VERSION 5.7 ;
  NOWIREEXTENSIONATPIN ON ;
  DIVIDERCHAR "/" ;
  BUSBITCHARS "[]" ;
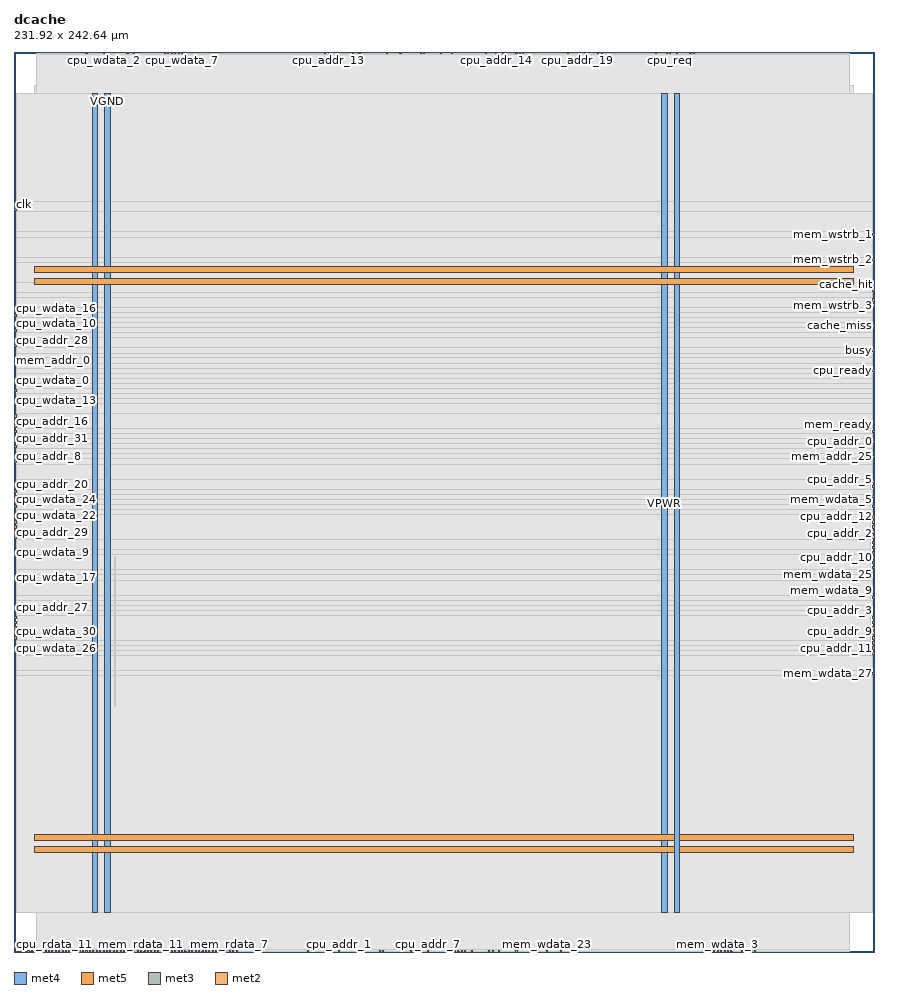
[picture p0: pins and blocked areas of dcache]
MACRO dcache
  CLASS BLOCK ;
  FOREIGN dcache ;
  ORIGIN 0.000 0.000 ;
  SIZE 231.920 BY 242.640 ;
  PIN VGND
    DIRECTION INOUT ;
    USE GROUND ;
    PORT
      LAYER met4 ;
        RECT 24.340 10.640 25.940 231.440 ;
    END
    PORT
      LAYER met4 ;
        RECT 177.940 10.640 179.540 231.440 ;
    END
    PORT
      LAYER met5 ;
        RECT 5.520 30.030 226.320 31.630 ;
    END
    PORT
      LAYER met5 ;
        RECT 5.520 183.210 226.320 184.810 ;
    END
  END VGND
  PIN VPWR
    DIRECTION INOUT ;
    USE POWER ;
    PORT
      LAYER met4 ;
        RECT 21.040 10.640 22.640 231.440 ;
    END
    PORT
      LAYER met4 ;
        RECT 174.640 10.640 176.240 231.440 ;
    END
    PORT
      LAYER met5 ;
        RECT 5.520 26.730 226.320 28.330 ;
    END
    PORT
      LAYER met5 ;
        RECT 5.520 179.910 226.320 181.510 ;
    END
  END VPWR
  PIN busy
    DIRECTION OUTPUT ;
    USE SIGNAL ;
    ANTENNAGATEAREA 0.434700 ;
    ANTENNADIFFAREA 0.434700 ;
    PORT
      LAYER met3 ;
        RECT 231.320 161.880 231.920 162.480 ;
    END
  END busy
  PIN cache_hit
    DIRECTION OUTPUT ;
    USE SIGNAL ;
    ANTENNAGATEAREA 0.434700 ;
    ANTENNADIFFAREA 1.137600 ;
    PORT
      LAYER met3 ;
        RECT 231.320 179.560 231.920 180.160 ;
    END
  END cache_hit
  PIN cache_miss
    DIRECTION OUTPUT ;
    USE SIGNAL ;
    ANTENNAGATEAREA 0.434700 ;
    ANTENNADIFFAREA 1.137600 ;
    PORT
      LAYER met3 ;
        RECT 231.320 168.680 231.920 169.280 ;
    END
  END cache_miss
  PIN clk
    DIRECTION INPUT ;
    USE SIGNAL ;
    ANTENNAGATEAREA 1.286700 ;
    ANTENNADIFFAREA 0.434700 ;
    PORT
      LAYER met3 ;
        RECT 0.000 201.320 0.600 201.920 ;
    END
  END clk
  PIN cpu_addr_0
    DIRECTION INPUT ;
    USE SIGNAL ;
    ANTENNAGATEAREA 0.647700 ;
    ANTENNADIFFAREA 0.434700 ;
    PORT
      LAYER met3 ;
        RECT 231.320 137.400 231.920 138.000 ;
    END
  END cpu_addr_0
  PIN cpu_addr_1
    DIRECTION INPUT ;
    USE SIGNAL ;
    ANTENNAGATEAREA 0.647700 ;
    ANTENNADIFFAREA 0.434700 ;
    PORT
      LAYER met2 ;
        RECT 87.490 0.000 87.770 0.280 ;
    END
  END cpu_addr_1
  PIN cpu_addr_10
    DIRECTION INPUT ;
    USE SIGNAL ;
    ANTENNAGATEAREA 0.647700 ;
    ANTENNADIFFAREA 0.434700 ;
    PORT
      LAYER met3 ;
        RECT 231.320 106.120 231.920 106.720 ;
    END
  END cpu_addr_10
  PIN cpu_addr_11
    DIRECTION INPUT ;
    USE SIGNAL ;
    ANTENNAGATEAREA 0.647700 ;
    ANTENNADIFFAREA 0.434700 ;
    PORT
      LAYER met3 ;
        RECT 231.320 81.640 231.920 82.240 ;
    END
  END cpu_addr_11
  PIN cpu_addr_12
    DIRECTION INPUT ;
    USE SIGNAL ;
    ANTENNAGATEAREA 0.647700 ;
    ANTENNADIFFAREA 0.434700 ;
    PORT
      LAYER met3 ;
        RECT 231.320 117.000 231.920 117.600 ;
    END
  END cpu_addr_12
  PIN cpu_addr_13
    DIRECTION INPUT ;
    USE SIGNAL ;
    ANTENNAGATEAREA 0.647700 ;
    ANTENNADIFFAREA 0.434700 ;
    PORT
      LAYER met2 ;
        RECT 84.730 242.360 85.010 242.640 ;
    END
  END cpu_addr_13
  PIN cpu_addr_14
    DIRECTION INPUT ;
    USE SIGNAL ;
    ANTENNAGATEAREA 0.647700 ;
    ANTENNADIFFAREA 0.434700 ;
    PORT
      LAYER met2 ;
        RECT 129.810 242.360 130.090 242.640 ;
    END
  END cpu_addr_14
  PIN cpu_addr_15
    DIRECTION INPUT ;
    USE SIGNAL ;
    ANTENNAGATEAREA 0.647700 ;
    ANTENNADIFFAREA 0.434700 ;
    PORT
      LAYER met2 ;
        RECT 110.490 242.360 110.770 242.640 ;
    END
  END cpu_addr_15
  PIN cpu_addr_16
    DIRECTION INPUT ;
    USE SIGNAL ;
    ANTENNAGATEAREA 0.647700 ;
    ANTENNADIFFAREA 0.434700 ;
    PORT
      LAYER met3 ;
        RECT 0.000 142.840 0.600 143.440 ;
    END
  END cpu_addr_16
  PIN cpu_addr_17
    DIRECTION INPUT ;
    USE SIGNAL ;
    ANTENNAGATEAREA 0.647700 ;
    ANTENNADIFFAREA 0.434700 ;
    PORT
      LAYER met2 ;
        RECT 130.730 242.360 131.010 242.640 ;
    END
  END cpu_addr_17
  PIN cpu_addr_18
    DIRECTION INPUT ;
    USE SIGNAL ;
    ANTENNAGATEAREA 0.647700 ;
    ANTENNADIFFAREA 0.434700 ;
    PORT
      LAYER met2 ;
        RECT 104.050 242.360 104.330 242.640 ;
    END
  END cpu_addr_18
  PIN cpu_addr_19
    DIRECTION INPUT ;
    USE SIGNAL ;
    ANTENNAGATEAREA 0.647700 ;
    ANTENNADIFFAREA 0.434700 ;
    PORT
      LAYER met2 ;
        RECT 151.890 242.360 152.170 242.640 ;
    END
  END cpu_addr_19
  PIN cpu_addr_2
    DIRECTION INPUT ;
    USE SIGNAL ;
    ANTENNAGATEAREA 0.647700 ;
    ANTENNADIFFAREA 0.434700 ;
    PORT
      LAYER met3 ;
        RECT 231.320 114.280 231.920 114.880 ;
    END
  END cpu_addr_2
  PIN cpu_addr_20
    DIRECTION INPUT ;
    USE SIGNAL ;
    ANTENNAGATEAREA 0.647700 ;
    ANTENNADIFFAREA 0.434700 ;
    PORT
      LAYER met3 ;
        RECT 0.000 123.800 0.600 124.400 ;
    END
  END cpu_addr_20
  PIN cpu_addr_21
    DIRECTION INPUT ;
    USE SIGNAL ;
    ANTENNAGATEAREA 0.647700 ;
    ANTENNADIFFAREA 0.434700 ;
    PORT
      LAYER met2 ;
        RECT 131.650 242.360 131.930 242.640 ;
    END
  END cpu_addr_21
  PIN cpu_addr_22
    DIRECTION INPUT ;
    USE SIGNAL ;
    ANTENNAGATEAREA 0.647700 ;
    ANTENNADIFFAREA 0.434700 ;
    PORT
      LAYER met2 ;
        RECT 40.570 242.360 40.850 242.640 ;
    END
  END cpu_addr_22
  PIN cpu_addr_23
    DIRECTION INPUT ;
    USE SIGNAL ;
    ANTENNAGATEAREA 0.647700 ;
    ANTENNADIFFAREA 0.434700 ;
    PORT
      LAYER met2 ;
        RECT 149.130 242.360 149.410 242.640 ;
    END
  END cpu_addr_23
  PIN cpu_addr_24
    DIRECTION INPUT ;
    USE SIGNAL ;
    ANTENNAGATEAREA 0.647700 ;
    ANTENNADIFFAREA 0.434700 ;
    PORT
      LAYER met2 ;
        RECT 99.450 0.000 99.730 0.280 ;
    END
  END cpu_addr_24
  PIN cpu_addr_25
    DIRECTION INPUT ;
    USE SIGNAL ;
    ANTENNAGATEAREA 0.647700 ;
    ANTENNADIFFAREA 0.434700 ;
    PORT
      LAYER met2 ;
        RECT 93.010 242.360 93.290 242.640 ;
    END
  END cpu_addr_25
  PIN cpu_addr_26
    DIRECTION INPUT ;
    USE SIGNAL ;
    ANTENNAGATEAREA 0.647700 ;
    ANTENNADIFFAREA 0.434700 ;
    PORT
      LAYER met2 ;
        RECT 115.090 242.360 115.370 242.640 ;
    END
  END cpu_addr_26
  PIN cpu_addr_27
    DIRECTION INPUT ;
    USE SIGNAL ;
    ANTENNAGATEAREA 0.647700 ;
    ANTENNADIFFAREA 0.434700 ;
    PORT
      LAYER met3 ;
        RECT 0.000 92.520 0.600 93.120 ;
    END
  END cpu_addr_27
  PIN cpu_addr_28
    DIRECTION INPUT ;
    USE SIGNAL ;
    ANTENNAGATEAREA 0.647700 ;
    ANTENNADIFFAREA 0.434700 ;
    PORT
      LAYER met3 ;
        RECT 0.000 164.600 0.600 165.200 ;
    END
  END cpu_addr_28
  PIN cpu_addr_29
    DIRECTION INPUT ;
    USE SIGNAL ;
    ANTENNAGATEAREA 0.647700 ;
    ANTENNADIFFAREA 0.434700 ;
    PORT
      LAYER met3 ;
        RECT 0.000 112.920 0.600 113.520 ;
    END
  END cpu_addr_29
  PIN cpu_addr_3
    DIRECTION INPUT ;
    USE SIGNAL ;
    ANTENNAGATEAREA 0.647700 ;
    ANTENNADIFFAREA 0.434700 ;
    PORT
      LAYER met3 ;
        RECT 231.320 89.800 231.920 90.400 ;
    END
  END cpu_addr_3
  PIN cpu_addr_30
    DIRECTION INPUT ;
    USE SIGNAL ;
    ANTENNAGATEAREA 0.647700 ;
    ANTENNADIFFAREA 0.434700 ;
    PORT
      LAYER met2 ;
        RECT 93.010 0.000 93.290 0.280 ;
    END
  END cpu_addr_30
  PIN cpu_addr_31
    DIRECTION INPUT ;
    USE SIGNAL ;
    ANTENNAGATEAREA 0.647700 ;
    ANTENNADIFFAREA 0.434700 ;
    PORT
      LAYER met3 ;
        RECT 0.000 140.120 0.600 140.720 ;
    END
  END cpu_addr_31
  PIN cpu_addr_4
    DIRECTION INPUT ;
    USE SIGNAL ;
    ANTENNAGATEAREA 0.647700 ;
    ANTENNADIFFAREA 0.434700 ;
    PORT
      LAYER met3 ;
        RECT 231.320 108.840 231.920 109.440 ;
    END
  END cpu_addr_4
  PIN cpu_addr_5
    DIRECTION INPUT ;
    USE SIGNAL ;
    ANTENNAGATEAREA 0.647700 ;
    ANTENNADIFFAREA 0.434700 ;
    PORT
      LAYER met3 ;
        RECT 231.320 125.160 231.920 125.760 ;
    END
  END cpu_addr_5
  PIN cpu_addr_6
    DIRECTION INPUT ;
    USE SIGNAL ;
    ANTENNAGATEAREA 0.647700 ;
    ANTENNADIFFAREA 0.434700 ;
    PORT
      LAYER met2 ;
        RECT 128.890 0.000 129.170 0.280 ;
    END
  END cpu_addr_6
  PIN cpu_addr_7
    DIRECTION INPUT ;
    USE SIGNAL ;
    ANTENNAGATEAREA 0.647700 ;
    ANTENNADIFFAREA 0.434700 ;
    PORT
      LAYER met2 ;
        RECT 111.410 0.000 111.690 0.280 ;
    END
  END cpu_addr_7
  PIN cpu_addr_8
    DIRECTION INPUT ;
    USE SIGNAL ;
    ANTENNAGATEAREA 0.647700 ;
    ANTENNADIFFAREA 0.434700 ;
    PORT
      LAYER met3 ;
        RECT 0.000 133.320 0.600 133.920 ;
    END
  END cpu_addr_8
  PIN cpu_addr_9
    DIRECTION INPUT ;
    USE SIGNAL ;
    ANTENNAGATEAREA 0.647700 ;
    ANTENNADIFFAREA 0.434700 ;
    PORT
      LAYER met3 ;
        RECT 231.320 84.360 231.920 84.960 ;
    END
  END cpu_addr_9
  PIN cpu_rdata_0
    DIRECTION OUTPUT ;
    USE SIGNAL ;
    PORT
      LAYER met2 ;
        RECT 1.930 0.000 2.210 0.280 ;
    END
  END cpu_rdata_0
  PIN cpu_rdata_1
    DIRECTION OUTPUT ;
    USE SIGNAL ;
    PORT
      LAYER met2 ;
        RECT 2.850 0.000 3.130 0.280 ;
    END
  END cpu_rdata_1
  PIN cpu_rdata_10
    DIRECTION OUTPUT ;
    USE SIGNAL ;
    PORT
      LAYER met2 ;
        RECT 3.770 0.000 4.050 0.280 ;
    END
  END cpu_rdata_10
  PIN cpu_rdata_11
    DIRECTION OUTPUT ;
    USE SIGNAL ;
    PORT
      LAYER met2 ;
        RECT 4.690 0.000 4.970 0.280 ;
    END
  END cpu_rdata_11
  PIN cpu_rdata_12
    DIRECTION OUTPUT ;
    USE SIGNAL ;
    PORT
      LAYER met2 ;
        RECT 5.610 0.000 5.890 0.280 ;
    END
  END cpu_rdata_12
  PIN cpu_rdata_13
    DIRECTION OUTPUT ;
    USE SIGNAL ;
    PORT
      LAYER met2 ;
        RECT 6.530 0.000 6.810 0.280 ;
    END
  END cpu_rdata_13
  PIN cpu_rdata_14
    DIRECTION OUTPUT ;
    USE SIGNAL ;
    PORT
      LAYER met2 ;
        RECT 7.450 0.000 7.730 0.280 ;
    END
  END cpu_rdata_14
  PIN cpu_rdata_15
    DIRECTION OUTPUT ;
    USE SIGNAL ;
    PORT
      LAYER met2 ;
        RECT 8.370 0.000 8.650 0.280 ;
    END
  END cpu_rdata_15
  PIN cpu_rdata_16
    DIRECTION OUTPUT ;
    USE SIGNAL ;
    PORT
      LAYER met2 ;
        RECT 9.290 0.000 9.570 0.280 ;
    END
  END cpu_rdata_16
  PIN cpu_rdata_17
    DIRECTION OUTPUT ;
    USE SIGNAL ;
    PORT
      LAYER met2 ;
        RECT 10.210 0.000 10.490 0.280 ;
    END
  END cpu_rdata_17
  PIN cpu_rdata_18
    DIRECTION OUTPUT ;
    USE SIGNAL ;
    PORT
      LAYER met2 ;
        RECT 11.130 0.000 11.410 0.280 ;
    END
  END cpu_rdata_18
  PIN cpu_rdata_19
    DIRECTION OUTPUT ;
    USE SIGNAL ;
    PORT
      LAYER met2 ;
        RECT 12.050 0.000 12.330 0.280 ;
    END
  END cpu_rdata_19
  PIN cpu_rdata_2
    DIRECTION OUTPUT ;
    USE SIGNAL ;
    PORT
      LAYER met2 ;
        RECT 12.970 0.000 13.250 0.280 ;
    END
  END cpu_rdata_2
  PIN cpu_rdata_20
    DIRECTION OUTPUT ;
    USE SIGNAL ;
    PORT
      LAYER met2 ;
        RECT 13.890 0.000 14.170 0.280 ;
    END
  END cpu_rdata_20
  PIN cpu_rdata_21
    DIRECTION OUTPUT ;
    USE SIGNAL ;
    PORT
      LAYER met2 ;
        RECT 14.810 0.000 15.090 0.280 ;
    END
  END cpu_rdata_21
  PIN cpu_rdata_22
    DIRECTION OUTPUT ;
    USE SIGNAL ;
    PORT
      LAYER met2 ;
        RECT 15.730 0.000 16.010 0.280 ;
    END
  END cpu_rdata_22
  PIN cpu_rdata_23
    DIRECTION OUTPUT ;
    USE SIGNAL ;
    PORT
      LAYER met2 ;
        RECT 16.650 0.000 16.930 0.280 ;
    END
  END cpu_rdata_23
  PIN cpu_rdata_24
    DIRECTION OUTPUT ;
    USE SIGNAL ;
    PORT
      LAYER met2 ;
        RECT 17.570 0.000 17.850 0.280 ;
    END
  END cpu_rdata_24
  PIN cpu_rdata_25
    DIRECTION OUTPUT ;
    USE SIGNAL ;
    PORT
      LAYER met2 ;
        RECT 18.490 0.000 18.770 0.280 ;
    END
  END cpu_rdata_25
  PIN cpu_rdata_26
    DIRECTION OUTPUT ;
    USE SIGNAL ;
    PORT
      LAYER met2 ;
        RECT 19.410 0.000 19.690 0.280 ;
    END
  END cpu_rdata_26
  PIN cpu_rdata_27
    DIRECTION OUTPUT ;
    USE SIGNAL ;
    PORT
      LAYER met2 ;
        RECT 20.330 0.000 20.610 0.280 ;
    END
  END cpu_rdata_27
  PIN cpu_rdata_28
    DIRECTION OUTPUT ;
    USE SIGNAL ;
    PORT
      LAYER met2 ;
        RECT 21.250 0.000 21.530 0.280 ;
    END
  END cpu_rdata_28
  PIN cpu_rdata_29
    DIRECTION OUTPUT ;
    USE SIGNAL ;
    PORT
      LAYER met2 ;
        RECT 22.170 0.000 22.450 0.280 ;
    END
  END cpu_rdata_29
  PIN cpu_rdata_3
    DIRECTION OUTPUT ;
    USE SIGNAL ;
    PORT
      LAYER met2 ;
        RECT 23.090 0.000 23.370 0.280 ;
    END
  END cpu_rdata_3
  PIN cpu_rdata_30
    DIRECTION OUTPUT ;
    USE SIGNAL ;
    PORT
      LAYER met2 ;
        RECT 24.010 0.000 24.290 0.280 ;
    END
  END cpu_rdata_30
  PIN cpu_rdata_31
    DIRECTION OUTPUT ;
    USE SIGNAL ;
    PORT
      LAYER met2 ;
        RECT 24.930 0.000 25.210 0.280 ;
    END
  END cpu_rdata_31
  PIN cpu_rdata_4
    DIRECTION OUTPUT ;
    USE SIGNAL ;
    PORT
      LAYER met2 ;
        RECT 25.850 0.000 26.130 0.280 ;
    END
  END cpu_rdata_4
  PIN cpu_rdata_5
    DIRECTION OUTPUT ;
    USE SIGNAL ;
    PORT
      LAYER met2 ;
        RECT 26.770 0.000 27.050 0.280 ;
    END
  END cpu_rdata_5
  PIN cpu_rdata_6
    DIRECTION OUTPUT ;
    USE SIGNAL ;
    PORT
      LAYER met2 ;
        RECT 27.690 0.000 27.970 0.280 ;
    END
  END cpu_rdata_6
  PIN cpu_rdata_7
    DIRECTION OUTPUT ;
    USE SIGNAL ;
    PORT
      LAYER met2 ;
        RECT 28.610 0.000 28.890 0.280 ;
    END
  END cpu_rdata_7
  PIN cpu_rdata_8
    DIRECTION OUTPUT ;
    USE SIGNAL ;
    PORT
      LAYER met2 ;
        RECT 29.530 0.000 29.810 0.280 ;
    END
  END cpu_rdata_8
  PIN cpu_rdata_9
    DIRECTION OUTPUT ;
    USE SIGNAL ;
    PORT
      LAYER met2 ;
        RECT 30.450 0.000 30.730 0.280 ;
    END
  END cpu_rdata_9
  PIN cpu_ready
    DIRECTION OUTPUT ;
    USE SIGNAL ;
    ANTENNAGATEAREA 0.434700 ;
    ANTENNADIFFAREA 1.137600 ;
    PORT
      LAYER met3 ;
        RECT 231.320 156.440 231.920 157.040 ;
    END
  END cpu_ready
  PIN cpu_req
    DIRECTION INPUT ;
    USE SIGNAL ;
    ANTENNAGATEAREA 0.647700 ;
    ANTENNADIFFAREA 0.434700 ;
    PORT
      LAYER met2 ;
        RECT 176.730 242.360 177.010 242.640 ;
    END
  END cpu_req
  PIN cpu_wdata_0
    DIRECTION INPUT ;
    USE SIGNAL ;
    ANTENNAGATEAREA 0.647700 ;
    ANTENNADIFFAREA 0.434700 ;
    PORT
      LAYER met3 ;
        RECT 0.000 153.720 0.600 154.320 ;
    END
  END cpu_wdata_0
  PIN cpu_wdata_1
    DIRECTION INPUT ;
    USE SIGNAL ;
    ANTENNAGATEAREA 0.647700 ;
    ANTENNADIFFAREA 0.434700 ;
    PORT
      LAYER met2 ;
        RECT 30.450 242.360 30.730 242.640 ;
    END
  END cpu_wdata_1
  PIN cpu_wdata_10
    DIRECTION INPUT ;
    USE SIGNAL ;
    ANTENNAGATEAREA 0.647700 ;
    ANTENNADIFFAREA 0.434700 ;
    PORT
      LAYER met3 ;
        RECT 0.000 167.320 0.600 167.920 ;
    END
  END cpu_wdata_10
  PIN cpu_wdata_11
    DIRECTION INPUT ;
    USE SIGNAL ;
    ANTENNAGATEAREA 0.647700 ;
    ANTENNADIFFAREA 0.434700 ;
    PORT
      LAYER met3 ;
        RECT 0.000 89.800 0.600 90.400 ;
    END
  END cpu_wdata_11
  PIN cpu_wdata_12
    DIRECTION INPUT ;
    USE SIGNAL ;
    ANTENNAGATEAREA 0.647700 ;
    ANTENNADIFFAREA 0.434700 ;
    PORT
      LAYER met3 ;
        RECT 0.000 168.680 0.600 169.280 ;
    END
  END cpu_wdata_12
  PIN cpu_wdata_13
    DIRECTION INPUT ;
    USE SIGNAL ;
    ANTENNAGATEAREA 0.647700 ;
    ANTENNADIFFAREA 0.434700 ;
    PORT
      LAYER met3 ;
        RECT 0.000 148.280 0.600 148.880 ;
    END
  END cpu_wdata_13
  PIN cpu_wdata_14
    DIRECTION INPUT ;
    USE SIGNAL ;
    ANTENNAGATEAREA 0.647700 ;
    ANTENNADIFFAREA 0.434700 ;
    PORT
      LAYER met2 ;
        RECT 44.250 242.360 44.530 242.640 ;
    END
  END cpu_wdata_14
  PIN cpu_wdata_15
    DIRECTION INPUT ;
    USE SIGNAL ;
    ANTENNAGATEAREA 0.647700 ;
    ANTENNADIFFAREA 0.434700 ;
    PORT
      LAYER met3 ;
        RECT 0.000 137.400 0.600 138.000 ;
    END
  END cpu_wdata_15
  PIN cpu_wdata_16
    DIRECTION INPUT ;
    USE SIGNAL ;
    ANTENNAGATEAREA 0.647700 ;
    ANTENNADIFFAREA 0.434700 ;
    PORT
      LAYER met3 ;
        RECT 0.000 171.400 0.600 172.000 ;
    END
  END cpu_wdata_16
  PIN cpu_wdata_17
    DIRECTION INPUT ;
    USE SIGNAL ;
    ANTENNAGATEAREA 0.647700 ;
    ANTENNADIFFAREA 0.434700 ;
    PORT
      LAYER met3 ;
        RECT 0.000 100.680 0.600 101.280 ;
    END
  END cpu_wdata_17
  PIN cpu_wdata_18
    DIRECTION INPUT ;
    USE SIGNAL ;
    ANTENNAGATEAREA 0.647700 ;
    ANTENNADIFFAREA 0.434700 ;
    PORT
      LAYER met3 ;
        RECT 0.000 151.000 0.600 151.600 ;
    END
  END cpu_wdata_18
  PIN cpu_wdata_19
    DIRECTION INPUT ;
    USE SIGNAL ;
    ANTENNAGATEAREA 0.647700 ;
    ANTENNADIFFAREA 0.434700 ;
    PORT
      LAYER met2 ;
        RECT 42.410 242.360 42.690 242.640 ;
    END
  END cpu_wdata_19
  PIN cpu_wdata_2
    DIRECTION INPUT ;
    USE SIGNAL ;
    ANTENNAGATEAREA 0.647700 ;
    ANTENNADIFFAREA 0.434700 ;
    PORT
      LAYER met2 ;
        RECT 24.010 242.360 24.290 242.640 ;
    END
  END cpu_wdata_2
  PIN cpu_wdata_20
    DIRECTION INPUT ;
    USE SIGNAL ;
    ANTENNAGATEAREA 0.647700 ;
    ANTENNADIFFAREA 0.434700 ;
    PORT
      LAYER met2 ;
        RECT 32.290 242.360 32.570 242.640 ;
    END
  END cpu_wdata_20
  PIN cpu_wdata_21
    DIRECTION INPUT ;
    USE SIGNAL ;
    ANTENNAGATEAREA 0.647700 ;
    ANTENNADIFFAREA 0.434700 ;
    PORT
      LAYER met3 ;
        RECT 0.000 87.080 0.600 87.680 ;
    END
  END cpu_wdata_21
  PIN cpu_wdata_22
    DIRECTION INPUT ;
    USE SIGNAL ;
    ANTENNAGATEAREA 0.647700 ;
    ANTENNADIFFAREA 0.434700 ;
    PORT
      LAYER met3 ;
        RECT 0.000 115.640 0.600 116.240 ;
    END
  END cpu_wdata_22
  PIN cpu_wdata_23
    DIRECTION INPUT ;
    USE SIGNAL ;
    ANTENNAGATEAREA 0.647700 ;
    ANTENNADIFFAREA 0.434700 ;
    PORT
      LAYER met2 ;
        RECT 24.930 242.360 25.210 242.640 ;
    END
  END cpu_wdata_23
  PIN cpu_wdata_24
    DIRECTION INPUT ;
    USE SIGNAL ;
    ANTENNAGATEAREA 0.647700 ;
    ANTENNADIFFAREA 0.434700 ;
    PORT
      LAYER met3 ;
        RECT 0.000 119.720 0.600 120.320 ;
    END
  END cpu_wdata_24
  PIN cpu_wdata_25
    DIRECTION INPUT ;
    USE SIGNAL ;
    ANTENNAGATEAREA 0.647700 ;
    ANTENNADIFFAREA 0.434700 ;
    PORT
      LAYER met3 ;
        RECT 0.000 111.560 0.600 112.160 ;
    END
  END cpu_wdata_25
  PIN cpu_wdata_26
    DIRECTION INPUT ;
    USE SIGNAL ;
    ANTENNAGATEAREA 0.647700 ;
    ANTENNADIFFAREA 0.434700 ;
    PORT
      LAYER met3 ;
        RECT 0.000 81.640 0.600 82.240 ;
    END
  END cpu_wdata_26
  PIN cpu_wdata_27
    DIRECTION INPUT ;
    USE SIGNAL ;
    ANTENNAGATEAREA 0.647700 ;
    ANTENNADIFFAREA 0.434700 ;
    PORT
      LAYER met3 ;
        RECT 0.000 88.440 0.600 89.040 ;
    END
  END cpu_wdata_27
  PIN cpu_wdata_28
    DIRECTION INPUT ;
    USE SIGNAL ;
    ANTENNAGATEAREA 0.647700 ;
    ANTENNADIFFAREA 0.434700 ;
    PORT
      LAYER met3 ;
        RECT 0.000 117.000 0.600 117.600 ;
    END
  END cpu_wdata_28
  PIN cpu_wdata_29
    DIRECTION INPUT ;
    USE SIGNAL ;
    ANTENNAGATEAREA 0.647700 ;
    ANTENNADIFFAREA 0.434700 ;
    PORT
      LAYER met2 ;
        RECT 19.410 242.360 19.690 242.640 ;
    END
  END cpu_wdata_29
  PIN cpu_wdata_3
    DIRECTION INPUT ;
    USE SIGNAL ;
    ANTENNAGATEAREA 0.647700 ;
    ANTENNADIFFAREA 0.434700 ;
    PORT
      LAYER met3 ;
        RECT 0.000 131.960 0.600 132.560 ;
    END
  END cpu_wdata_3
  PIN cpu_wdata_30
    DIRECTION INPUT ;
    USE SIGNAL ;
    ANTENNAGATEAREA 0.647700 ;
    ANTENNADIFFAREA 0.434700 ;
    PORT
      LAYER met3 ;
        RECT 0.000 84.360 0.600 84.960 ;
    END
  END cpu_wdata_30
  PIN cpu_wdata_31
    DIRECTION INPUT ;
    USE SIGNAL ;
    ANTENNAGATEAREA 0.647700 ;
    ANTENNADIFFAREA 0.434700 ;
    PORT
      LAYER met2 ;
        RECT 157.410 242.360 157.690 242.640 ;
    END
  END cpu_wdata_31
  PIN cpu_wdata_4
    DIRECTION INPUT ;
    USE SIGNAL ;
    ANTENNAGATEAREA 0.647700 ;
    ANTENNADIFFAREA 0.434700 ;
    PORT
      LAYER met2 ;
        RECT 43.330 242.360 43.610 242.640 ;
    END
  END cpu_wdata_4
  PIN cpu_wdata_5
    DIRECTION INPUT ;
    USE SIGNAL ;
    ANTENNAGATEAREA 0.647700 ;
    ANTENNADIFFAREA 0.434700 ;
    PORT
      LAYER met3 ;
        RECT 0.000 136.040 0.600 136.640 ;
    END
  END cpu_wdata_5
  PIN cpu_wdata_6
    DIRECTION INPUT ;
    USE SIGNAL ;
    ANTENNAGATEAREA 0.647700 ;
    ANTENNADIFFAREA 0.434700 ;
    PORT
      LAYER met3 ;
        RECT 0.000 85.720 0.600 86.320 ;
    END
  END cpu_wdata_6
  PIN cpu_wdata_7
    DIRECTION INPUT ;
    USE SIGNAL ;
    ANTENNAGATEAREA 0.647700 ;
    ANTENNADIFFAREA 0.434700 ;
    PORT
      LAYER met2 ;
        RECT 45.170 242.360 45.450 242.640 ;
    END
  END cpu_wdata_7
  PIN cpu_wdata_8
    DIRECTION INPUT ;
    USE SIGNAL ;
    ANTENNAGATEAREA 0.647700 ;
    ANTENNADIFFAREA 0.434700 ;
    PORT
      LAYER met3 ;
        RECT 0.000 144.200 0.600 144.800 ;
    END
  END cpu_wdata_8
  PIN cpu_wdata_9
    DIRECTION INPUT ;
    USE SIGNAL ;
    ANTENNAGATEAREA 0.647700 ;
    ANTENNADIFFAREA 0.434700 ;
    PORT
      LAYER met3 ;
        RECT 0.000 107.480 0.600 108.080 ;
    END
  END cpu_wdata_9
  PIN cpu_wstrb_0
    DIRECTION INPUT ;
    USE SIGNAL ;
    ANTENNAGATEAREA 0.647700 ;
    ANTENNADIFFAREA 0.434700 ;
    PORT
      LAYER met2 ;
        RECT 183.170 242.360 183.450 242.640 ;
    END
  END cpu_wstrb_0
  PIN cpu_wstrb_1
    DIRECTION INPUT ;
    USE SIGNAL ;
    ANTENNAGATEAREA 0.647700 ;
    ANTENNADIFFAREA 0.434700 ;
    PORT
      LAYER met2 ;
        RECT 182.250 242.360 182.530 242.640 ;
    END
  END cpu_wstrb_1
  PIN cpu_wstrb_2
    DIRECTION INPUT ;
    USE SIGNAL ;
    ANTENNAGATEAREA 0.647700 ;
    ANTENNADIFFAREA 0.434700 ;
    PORT
      LAYER met2 ;
        RECT 178.570 242.360 178.850 242.640 ;
    END
  END cpu_wstrb_2
  PIN cpu_wstrb_3
    DIRECTION INPUT ;
    USE SIGNAL ;
    ANTENNAGATEAREA 0.647700 ;
    ANTENNADIFFAREA 0.434700 ;
    PORT
      LAYER met2 ;
        RECT 173.050 242.360 173.330 242.640 ;
    END
  END cpu_wstrb_3
  PIN flush
    DIRECTION INPUT ;
    USE SIGNAL ;
    ANTENNAGATEAREA 0.647700 ;
    ANTENNADIFFAREA 0.434700 ;
    PORT
      LAYER met2 ;
        RECT 175.810 242.360 176.090 242.640 ;
    END
  END flush
  PIN mem_addr_0
    DIRECTION OUTPUT ;
    USE SIGNAL ;
    ANTENNAGATEAREA 0.434700 ;
    ANTENNADIFFAREA 1.137600 ;
    PORT
      LAYER met3 ;
        RECT 0.000 159.160 0.600 159.760 ;
    END
  END mem_addr_0
  PIN mem_addr_1
    DIRECTION OUTPUT ;
    USE SIGNAL ;
    ANTENNAGATEAREA 0.434700 ;
    ANTENNADIFFAREA 1.137600 ;
    PORT
      LAYER met2 ;
        RECT 41.490 242.360 41.770 242.640 ;
    END
  END mem_addr_1
  PIN mem_addr_10
    DIRECTION OUTPUT ;
    USE SIGNAL ;
    ANTENNAGATEAREA 0.434700 ;
    ANTENNADIFFAREA 1.137600 ;
    PORT
      LAYER met2 ;
        RECT 153.730 242.360 154.010 242.640 ;
    END
  END mem_addr_10
  PIN mem_addr_11
    DIRECTION OUTPUT ;
    USE SIGNAL ;
    ANTENNAGATEAREA 0.434700 ;
    ANTENNADIFFAREA 1.137600 ;
    PORT
      LAYER met2 ;
        RECT 83.810 242.360 84.090 242.640 ;
    END
  END mem_addr_11
  PIN mem_addr_12
    DIRECTION OUTPUT ;
    USE SIGNAL ;
    ANTENNAGATEAREA 0.434700 ;
    ANTENNADIFFAREA 1.137600 ;
    PORT
      LAYER met2 ;
        RECT 135.330 242.360 135.610 242.640 ;
    END
  END mem_addr_12
  PIN mem_addr_13
    DIRECTION OUTPUT ;
    USE SIGNAL ;
    ANTENNAGATEAREA 0.434700 ;
    ANTENNADIFFAREA 1.137600 ;
    PORT
      LAYER met3 ;
        RECT 0.000 122.440 0.600 123.040 ;
    END
  END mem_addr_13
  PIN mem_addr_14
    DIRECTION OUTPUT ;
    USE SIGNAL ;
    ANTENNAGATEAREA 0.434700 ;
    ANTENNADIFFAREA 1.137600 ;
    PORT
      LAYER met2 ;
        RECT 158.330 242.360 158.610 242.640 ;
    END
  END mem_addr_14
  PIN mem_addr_15
    DIRECTION OUTPUT ;
    USE SIGNAL ;
    ANTENNAGATEAREA 0.434700 ;
    ANTENNADIFFAREA 1.137600 ;
    PORT
      LAYER met2 ;
        RECT 109.570 242.360 109.850 242.640 ;
    END
  END mem_addr_15
  PIN mem_addr_16
    DIRECTION OUTPUT ;
    USE SIGNAL ;
    ANTENNAGATEAREA 0.434700 ;
    ANTENNADIFFAREA 1.137600 ;
    PORT
      LAYER met2 ;
        RECT 136.250 242.360 136.530 242.640 ;
    END
  END mem_addr_16
  PIN mem_addr_17
    DIRECTION OUTPUT ;
    USE SIGNAL ;
    ANTENNAGATEAREA 0.434700 ;
    ANTENNADIFFAREA 1.137600 ;
    PORT
      LAYER met3 ;
        RECT 0.000 141.480 0.600 142.080 ;
    END
  END mem_addr_17
  PIN mem_addr_18
    DIRECTION OUTPUT ;
    USE SIGNAL ;
    ANTENNAGATEAREA 0.434700 ;
    ANTENNADIFFAREA 1.137600 ;
    PORT
      LAYER met2 ;
        RECT 117.850 242.360 118.130 242.640 ;
    END
  END mem_addr_18
  PIN mem_addr_19
    DIRECTION OUTPUT ;
    USE SIGNAL ;
    ANTENNAGATEAREA 0.434700 ;
    ANTENNADIFFAREA 1.137600 ;
    PORT
      LAYER met2 ;
        RECT 137.170 242.360 137.450 242.640 ;
    END
  END mem_addr_19
  PIN mem_addr_2
    DIRECTION OUTPUT ;
    USE SIGNAL ;
    ANTENNAGATEAREA 0.434700 ;
    ANTENNADIFFAREA 1.137600 ;
    PORT
      LAYER met3 ;
        RECT 0.000 138.760 0.600 139.360 ;
    END
  END mem_addr_2
  PIN mem_addr_20
    DIRECTION OUTPUT ;
    USE SIGNAL ;
    ANTENNAGATEAREA 0.434700 ;
    ANTENNADIFFAREA 1.137600 ;
    PORT
      LAYER met2 ;
        RECT 91.170 242.360 91.450 242.640 ;
    END
  END mem_addr_20
  PIN mem_addr_21
    DIRECTION OUTPUT ;
    USE SIGNAL ;
    ANTENNAGATEAREA 0.434700 ;
    ANTENNADIFFAREA 1.137600 ;
    PORT
      LAYER met3 ;
        RECT 231.320 111.560 231.920 112.160 ;
    END
  END mem_addr_21
  PIN mem_addr_22
    DIRECTION OUTPUT ;
    USE SIGNAL ;
    ANTENNAGATEAREA 0.434700 ;
    ANTENNADIFFAREA 1.137600 ;
    PORT
      LAYER met3 ;
        RECT 231.320 80.280 231.920 80.880 ;
    END
  END mem_addr_22
  PIN mem_addr_23
    DIRECTION OUTPUT ;
    USE SIGNAL ;
    ANTENNAGATEAREA 0.434700 ;
    ANTENNADIFFAREA 1.137600 ;
    PORT
      LAYER met3 ;
        RECT 231.320 104.760 231.920 105.360 ;
    END
  END mem_addr_23
  PIN mem_addr_24
    DIRECTION OUTPUT ;
    USE SIGNAL ;
    ANTENNAGATEAREA 0.434700 ;
    ANTENNADIFFAREA 1.137600 ;
    PORT
      LAYER met3 ;
        RECT 231.320 83.000 231.920 83.600 ;
    END
  END mem_addr_24
  PIN mem_addr_25
    DIRECTION OUTPUT ;
    USE SIGNAL ;
    ANTENNAGATEAREA 0.434700 ;
    ANTENNADIFFAREA 1.137600 ;
    PORT
      LAYER met3 ;
        RECT 231.320 133.320 231.920 133.920 ;
    END
  END mem_addr_25
  PIN mem_addr_26
    DIRECTION OUTPUT ;
    USE SIGNAL ;
    ANTENNAGATEAREA 0.434700 ;
    ANTENNADIFFAREA 1.137600 ;
    PORT
      LAYER met2 ;
        RECT 118.770 0.000 119.050 0.280 ;
    END
  END mem_addr_26
  PIN mem_addr_27
    DIRECTION OUTPUT ;
    USE SIGNAL ;
    ANTENNAGATEAREA 0.434700 ;
    ANTENNADIFFAREA 1.137600 ;
    PORT
      LAYER met2 ;
        RECT 135.330 0.000 135.610 0.280 ;
    END
  END mem_addr_27
  PIN mem_addr_28
    DIRECTION OUTPUT ;
    USE SIGNAL ;
    ANTENNAGATEAREA 0.434700 ;
    ANTENNADIFFAREA 1.137600 ;
    PORT
      LAYER met3 ;
        RECT 231.320 126.520 231.920 127.120 ;
    END
  END mem_addr_28
  PIN mem_addr_29
    DIRECTION OUTPUT ;
    USE SIGNAL ;
    ANTENNAGATEAREA 0.434700 ;
    ANTENNADIFFAREA 1.137600 ;
    PORT
      LAYER met3 ;
        RECT 231.320 107.480 231.920 108.080 ;
    END
  END mem_addr_29
  PIN mem_addr_3
    DIRECTION OUTPUT ;
    USE SIGNAL ;
    ANTENNAGATEAREA 0.434700 ;
    ANTENNADIFFAREA 1.137600 ;
    PORT
      LAYER met2 ;
        RECT 98.530 0.000 98.810 0.280 ;
    END
  END mem_addr_3
  PIN mem_addr_30
    DIRECTION OUTPUT ;
    USE SIGNAL ;
    ANTENNAGATEAREA 0.434700 ;
    ANTENNADIFFAREA 1.137600 ;
    PORT
      LAYER met3 ;
        RECT 231.320 88.440 231.920 89.040 ;
    END
  END mem_addr_30
  PIN mem_addr_31
    DIRECTION OUTPUT ;
    USE SIGNAL ;
    ANTENNAGATEAREA 0.434700 ;
    ANTENNADIFFAREA 1.137600 ;
    PORT
      LAYER met3 ;
        RECT 231.320 112.920 231.920 113.520 ;
    END
  END mem_addr_31
  PIN mem_addr_4
    DIRECTION OUTPUT ;
    USE SIGNAL ;
    ANTENNAGATEAREA 0.434700 ;
    ANTENNADIFFAREA 1.137600 ;
    PORT
      LAYER met3 ;
        RECT 0.000 114.280 0.600 114.880 ;
    END
  END mem_addr_4
  PIN mem_addr_5
    DIRECTION OUTPUT ;
    USE SIGNAL ;
    ANTENNAGATEAREA 0.434700 ;
    ANTENNADIFFAREA 1.137600 ;
    PORT
      LAYER met3 ;
        RECT 0.000 163.240 0.600 163.840 ;
    END
  END mem_addr_5
  PIN mem_addr_6
    DIRECTION OUTPUT ;
    USE SIGNAL ;
    ANTENNAGATEAREA 0.434700 ;
    ANTENNADIFFAREA 1.137600 ;
    PORT
      LAYER met2 ;
        RECT 79.210 0.000 79.490 0.280 ;
    END
  END mem_addr_6
  PIN mem_addr_7
    DIRECTION OUTPUT ;
    USE SIGNAL ;
    ANTENNAGATEAREA 0.434700 ;
    ANTENNADIFFAREA 1.137600 ;
    PORT
      LAYER met2 ;
        RECT 127.050 242.360 127.330 242.640 ;
    END
  END mem_addr_7
  PIN mem_addr_8
    DIRECTION OUTPUT ;
    USE SIGNAL ;
    ANTENNAGATEAREA 0.434700 ;
    ANTENNADIFFAREA 1.137600 ;
    PORT
      LAYER met2 ;
        RECT 100.370 242.360 100.650 242.640 ;
    END
  END mem_addr_8
  PIN mem_addr_9
    DIRECTION OUTPUT ;
    USE SIGNAL ;
    ANTENNAGATEAREA 0.434700 ;
    ANTENNADIFFAREA 1.137600 ;
    PORT
      LAYER met2 ;
        RECT 106.810 0.000 107.090 0.280 ;
    END
  END mem_addr_9
  PIN mem_rdata_0
    DIRECTION INPUT ;
    USE SIGNAL ;
    PORT
      LAYER met2 ;
        RECT 31.370 0.000 31.650 0.280 ;
    END
  END mem_rdata_0
  PIN mem_rdata_1
    DIRECTION INPUT ;
    USE SIGNAL ;
    PORT
      LAYER met2 ;
        RECT 32.290 0.000 32.570 0.280 ;
    END
  END mem_rdata_1
  PIN mem_rdata_10
    DIRECTION INPUT ;
    USE SIGNAL ;
    PORT
      LAYER met2 ;
        RECT 33.210 0.000 33.490 0.280 ;
    END
  END mem_rdata_10
  PIN mem_rdata_11
    DIRECTION INPUT ;
    USE SIGNAL ;
    PORT
      LAYER met2 ;
        RECT 34.130 0.000 34.410 0.280 ;
    END
  END mem_rdata_11
  PIN mem_rdata_12
    DIRECTION INPUT ;
    USE SIGNAL ;
    PORT
      LAYER met2 ;
        RECT 35.050 0.000 35.330 0.280 ;
    END
  END mem_rdata_12
  PIN mem_rdata_13
    DIRECTION INPUT ;
    USE SIGNAL ;
    PORT
      LAYER met2 ;
        RECT 35.970 0.000 36.250 0.280 ;
    END
  END mem_rdata_13
  PIN mem_rdata_14
    DIRECTION INPUT ;
    USE SIGNAL ;
    PORT
      LAYER met2 ;
        RECT 36.890 0.000 37.170 0.280 ;
    END
  END mem_rdata_14
  PIN mem_rdata_15
    DIRECTION INPUT ;
    USE SIGNAL ;
    PORT
      LAYER met2 ;
        RECT 37.810 0.000 38.090 0.280 ;
    END
  END mem_rdata_15
  PIN mem_rdata_16
    DIRECTION INPUT ;
    USE SIGNAL ;
    PORT
      LAYER met2 ;
        RECT 38.730 0.000 39.010 0.280 ;
    END
  END mem_rdata_16
  PIN mem_rdata_17
    DIRECTION INPUT ;
    USE SIGNAL ;
    PORT
      LAYER met2 ;
        RECT 39.650 0.000 39.930 0.280 ;
    END
  END mem_rdata_17
  PIN mem_rdata_18
    DIRECTION INPUT ;
    USE SIGNAL ;
    PORT
      LAYER met2 ;
        RECT 40.570 0.000 40.850 0.280 ;
    END
  END mem_rdata_18
  PIN mem_rdata_19
    DIRECTION INPUT ;
    USE SIGNAL ;
    PORT
      LAYER met2 ;
        RECT 41.490 0.000 41.770 0.280 ;
    END
  END mem_rdata_19
  PIN mem_rdata_2
    DIRECTION INPUT ;
    USE SIGNAL ;
    PORT
      LAYER met2 ;
        RECT 42.410 0.000 42.690 0.280 ;
    END
  END mem_rdata_2
  PIN mem_rdata_20
    DIRECTION INPUT ;
    USE SIGNAL ;
    PORT
      LAYER met2 ;
        RECT 43.330 0.000 43.610 0.280 ;
    END
  END mem_rdata_20
  PIN mem_rdata_21
    DIRECTION INPUT ;
    USE SIGNAL ;
    PORT
      LAYER met2 ;
        RECT 44.250 0.000 44.530 0.280 ;
    END
  END mem_rdata_21
  PIN mem_rdata_22
    DIRECTION INPUT ;
    USE SIGNAL ;
    PORT
      LAYER met2 ;
        RECT 45.170 0.000 45.450 0.280 ;
    END
  END mem_rdata_22
  PIN mem_rdata_23
    DIRECTION INPUT ;
    USE SIGNAL ;
    PORT
      LAYER met2 ;
        RECT 46.090 0.000 46.370 0.280 ;
    END
  END mem_rdata_23
  PIN mem_rdata_24
    DIRECTION INPUT ;
    USE SIGNAL ;
    PORT
      LAYER met2 ;
        RECT 47.010 0.000 47.290 0.280 ;
    END
  END mem_rdata_24
  PIN mem_rdata_25
    DIRECTION INPUT ;
    USE SIGNAL ;
    PORT
      LAYER met2 ;
        RECT 47.930 0.000 48.210 0.280 ;
    END
  END mem_rdata_25
  PIN mem_rdata_26
    DIRECTION INPUT ;
    USE SIGNAL ;
    PORT
      LAYER met2 ;
        RECT 48.850 0.000 49.130 0.280 ;
    END
  END mem_rdata_26
  PIN mem_rdata_27
    DIRECTION INPUT ;
    USE SIGNAL ;
    PORT
      LAYER met2 ;
        RECT 49.770 0.000 50.050 0.280 ;
    END
  END mem_rdata_27
  PIN mem_rdata_28
    DIRECTION INPUT ;
    USE SIGNAL ;
    PORT
      LAYER met2 ;
        RECT 50.690 0.000 50.970 0.280 ;
    END
  END mem_rdata_28
  PIN mem_rdata_29
    DIRECTION INPUT ;
    USE SIGNAL ;
    PORT
      LAYER met2 ;
        RECT 51.610 0.000 51.890 0.280 ;
    END
  END mem_rdata_29
  PIN mem_rdata_3
    DIRECTION INPUT ;
    USE SIGNAL ;
    PORT
      LAYER met2 ;
        RECT 52.530 0.000 52.810 0.280 ;
    END
  END mem_rdata_3
  PIN mem_rdata_30
    DIRECTION INPUT ;
    USE SIGNAL ;
    PORT
      LAYER met2 ;
        RECT 53.450 0.000 53.730 0.280 ;
    END
  END mem_rdata_30
  PIN mem_rdata_31
    DIRECTION INPUT ;
    USE SIGNAL ;
    PORT
      LAYER met2 ;
        RECT 54.370 0.000 54.650 0.280 ;
    END
  END mem_rdata_31
  PIN mem_rdata_4
    DIRECTION INPUT ;
    USE SIGNAL ;
    PORT
      LAYER met2 ;
        RECT 55.290 0.000 55.570 0.280 ;
    END
  END mem_rdata_4
  PIN mem_rdata_5
    DIRECTION INPUT ;
    USE SIGNAL ;
    PORT
      LAYER met2 ;
        RECT 56.210 0.000 56.490 0.280 ;
    END
  END mem_rdata_5
  PIN mem_rdata_6
    DIRECTION INPUT ;
    USE SIGNAL ;
    PORT
      LAYER met2 ;
        RECT 57.130 0.000 57.410 0.280 ;
    END
  END mem_rdata_6
  PIN mem_rdata_7
    DIRECTION INPUT ;
    USE SIGNAL ;
    PORT
      LAYER met2 ;
        RECT 58.050 0.000 58.330 0.280 ;
    END
  END mem_rdata_7
  PIN mem_rdata_8
    DIRECTION INPUT ;
    USE SIGNAL ;
    PORT
      LAYER met2 ;
        RECT 58.970 0.000 59.250 0.280 ;
    END
  END mem_rdata_8
  PIN mem_rdata_9
    DIRECTION INPUT ;
    USE SIGNAL ;
    PORT
      LAYER met2 ;
        RECT 59.890 0.000 60.170 0.280 ;
    END
  END mem_rdata_9
  PIN mem_ready
    DIRECTION INPUT ;
    USE SIGNAL ;
    ANTENNAGATEAREA 0.647700 ;
    ANTENNADIFFAREA 0.434700 ;
    PORT
      LAYER met3 ;
        RECT 231.320 140.120 231.920 140.720 ;
    END
  END mem_ready
  PIN mem_req
    DIRECTION OUTPUT ;
    USE SIGNAL ;
    ANTENNAGATEAREA 0.434700 ;
    ANTENNADIFFAREA 1.137600 ;
    PORT
      LAYER met3 ;
        RECT 231.320 178.200 231.920 178.800 ;
    END
  END mem_req
  PIN mem_wdata_0
    DIRECTION OUTPUT ;
    USE SIGNAL ;
    ANTENNAGATEAREA 0.434700 ;
    ANTENNADIFFAREA 1.137600 ;
    PORT
      LAYER met2 ;
        RECT 193.290 0.000 193.570 0.280 ;
    END
  END mem_wdata_0
  PIN mem_wdata_1
    DIRECTION OUTPUT ;
    USE SIGNAL ;
    ANTENNAGATEAREA 0.434700 ;
    ANTENNADIFFAREA 1.137600 ;
    PORT
      LAYER met2 ;
        RECT 120.610 0.000 120.890 0.280 ;
    END
  END mem_wdata_1
  PIN mem_wdata_10
    DIRECTION OUTPUT ;
    USE SIGNAL ;
    ANTENNAGATEAREA 0.434700 ;
    ANTENNADIFFAREA 1.137600 ;
    PORT
      LAYER met2 ;
        RECT 198.810 0.000 199.090 0.280 ;
    END
  END mem_wdata_10
  PIN mem_wdata_11
    DIRECTION OUTPUT ;
    USE SIGNAL ;
    ANTENNAGATEAREA 0.434700 ;
    ANTENNADIFFAREA 1.137600 ;
    PORT
      LAYER met2 ;
        RECT 186.850 0.000 187.130 0.280 ;
    END
  END mem_wdata_11
  PIN mem_wdata_12
    DIRECTION OUTPUT ;
    USE SIGNAL ;
    ANTENNAGATEAREA 0.434700 ;
    ANTENNADIFFAREA 1.137600 ;
    PORT
      LAYER met2 ;
        RECT 192.370 0.000 192.650 0.280 ;
    END
  END mem_wdata_12
  PIN mem_wdata_13
    DIRECTION OUTPUT ;
    USE SIGNAL ;
    ANTENNAGATEAREA 0.434700 ;
    ANTENNADIFFAREA 1.137600 ;
    PORT
      LAYER met2 ;
        RECT 147.290 0.000 147.570 0.280 ;
    END
  END mem_wdata_13
  PIN mem_wdata_14
    DIRECTION OUTPUT ;
    USE SIGNAL ;
    ANTENNAGATEAREA 0.434700 ;
    ANTENNADIFFAREA 1.137600 ;
    PORT
      LAYER met2 ;
        RECT 127.970 0.000 128.250 0.280 ;
    END
  END mem_wdata_14
  PIN mem_wdata_15
    DIRECTION OUTPUT ;
    USE SIGNAL ;
    ANTENNAGATEAREA 0.434700 ;
    ANTENNADIFFAREA 1.137600 ;
    PORT
      LAYER met2 ;
        RECT 130.730 0.000 131.010 0.280 ;
    END
  END mem_wdata_15
  PIN mem_wdata_16
    DIRECTION OUTPUT ;
    USE SIGNAL ;
    ANTENNAGATEAREA 0.434700 ;
    ANTENNADIFFAREA 1.137600 ;
    PORT
      LAYER met2 ;
        RECT 196.970 0.000 197.250 0.280 ;
    END
  END mem_wdata_16
  PIN mem_wdata_17
    DIRECTION OUTPUT ;
    USE SIGNAL ;
    ANTENNAGATEAREA 0.434700 ;
    ANTENNADIFFAREA 1.137600 ;
    PORT
      LAYER met3 ;
        RECT 231.320 115.640 231.920 116.240 ;
    END
  END mem_wdata_17
  PIN mem_wdata_18
    DIRECTION OUTPUT ;
    USE SIGNAL ;
    ANTENNAGATEAREA 0.434700 ;
    ANTENNADIFFAREA 1.137600 ;
    PORT
      LAYER met2 ;
        RECT 190.530 0.000 190.810 0.280 ;
    END
  END mem_wdata_18
  PIN mem_wdata_19
    DIRECTION OUTPUT ;
    USE SIGNAL ;
    ANTENNAGATEAREA 0.434700 ;
    ANTENNADIFFAREA 1.137600 ;
    PORT
      LAYER met2 ;
        RECT 121.530 0.000 121.810 0.280 ;
    END
  END mem_wdata_19
  PIN mem_wdata_2
    DIRECTION OUTPUT ;
    USE SIGNAL ;
    ANTENNAGATEAREA 0.434700 ;
    ANTENNADIFFAREA 1.137600 ;
    PORT
      LAYER met2 ;
        RECT 199.730 0.000 200.010 0.280 ;
    END
  END mem_wdata_2
  PIN mem_wdata_20
    DIRECTION OUTPUT ;
    USE SIGNAL ;
    ANTENNAGATEAREA 0.434700 ;
    ANTENNADIFFAREA 1.137600 ;
    PORT
      LAYER met3 ;
        RECT 231.320 87.080 231.920 87.680 ;
    END
  END mem_wdata_20
  PIN mem_wdata_21
    DIRECTION OUTPUT ;
    USE SIGNAL ;
    ANTENNAGATEAREA 0.434700 ;
    ANTENNADIFFAREA 1.137600 ;
    PORT
      LAYER met2 ;
        RECT 187.770 0.000 188.050 0.280 ;
    END
  END mem_wdata_21
  PIN mem_wdata_22
    DIRECTION OUTPUT ;
    USE SIGNAL ;
    ANTENNAGATEAREA 0.434700 ;
    ANTENNADIFFAREA 1.137600 ;
    PORT
      LAYER met2 ;
        RECT 123.370 0.000 123.650 0.280 ;
    END
  END mem_wdata_22
  PIN mem_wdata_23
    DIRECTION OUTPUT ;
    USE SIGNAL ;
    ANTENNAGATEAREA 0.434700 ;
    ANTENNADIFFAREA 1.137600 ;
    PORT
      LAYER met2 ;
        RECT 143.610 0.000 143.890 0.280 ;
    END
  END mem_wdata_23
  PIN mem_wdata_24
    DIRECTION OUTPUT ;
    USE SIGNAL ;
    ANTENNAGATEAREA 0.434700 ;
    ANTENNADIFFAREA 1.137600 ;
    PORT
      LAYER met3 ;
        RECT 231.320 85.720 231.920 86.320 ;
    END
  END mem_wdata_24
  PIN mem_wdata_25
    DIRECTION OUTPUT ;
    USE SIGNAL ;
    ANTENNAGATEAREA 0.434700 ;
    ANTENNADIFFAREA 1.137600 ;
    PORT
      LAYER met3 ;
        RECT 231.320 103.400 231.920 104.000 ;
    END
  END mem_wdata_25
  PIN mem_wdata_26
    DIRECTION OUTPUT ;
    USE SIGNAL ;
    ANTENNAGATEAREA 0.434700 ;
    ANTENNADIFFAREA 1.137600 ;
    PORT
      LAYER met2 ;
        RECT 196.050 0.000 196.330 0.280 ;
    END
  END mem_wdata_26
  PIN mem_wdata_27
    DIRECTION OUTPUT ;
    USE SIGNAL ;
    ANTENNAGATEAREA 0.434700 ;
    ANTENNADIFFAREA 1.137600 ;
    PORT
      LAYER met3 ;
        RECT 231.320 74.840 231.920 75.440 ;
    END
  END mem_wdata_27
  PIN mem_wdata_28
    DIRECTION OUTPUT ;
    USE SIGNAL ;
    ANTENNAGATEAREA 0.434700 ;
    ANTENNADIFFAREA 1.137600 ;
    PORT
      LAYER met2 ;
        RECT 140.850 0.000 141.130 0.280 ;
    END
  END mem_wdata_28
  PIN mem_wdata_29
    DIRECTION OUTPUT ;
    USE SIGNAL ;
    ANTENNAGATEAREA 0.434700 ;
    ANTENNADIFFAREA 1.137600 ;
    PORT
      LAYER met2 ;
        RECT 185.930 0.000 186.210 0.280 ;
    END
  END mem_wdata_29
  PIN mem_wdata_3
    DIRECTION OUTPUT ;
    USE SIGNAL ;
    ANTENNAGATEAREA 0.434700 ;
    ANTENNADIFFAREA 1.137600 ;
    PORT
      LAYER met2 ;
        RECT 189.610 0.000 189.890 0.280 ;
    END
  END mem_wdata_3
  PIN mem_wdata_30
    DIRECTION OUTPUT ;
    USE SIGNAL ;
    ANTENNAGATEAREA 0.434700 ;
    ANTENNADIFFAREA 1.137600 ;
    PORT
      LAYER met2 ;
        RECT 191.450 0.000 191.730 0.280 ;
    END
  END mem_wdata_30
  PIN mem_wdata_31
    DIRECTION OUTPUT ;
    USE SIGNAL ;
    ANTENNAGATEAREA 0.434700 ;
    ANTENNADIFFAREA 1.137600 ;
    PORT
      LAYER met2 ;
        RECT 197.890 0.000 198.170 0.280 ;
    END
  END mem_wdata_31
  PIN mem_wdata_4
    DIRECTION OUTPUT ;
    USE SIGNAL ;
    ANTENNAGATEAREA 0.434700 ;
    ANTENNADIFFAREA 1.137600 ;
    PORT
      LAYER met3 ;
        RECT 231.320 122.440 231.920 123.040 ;
    END
  END mem_wdata_4
  PIN mem_wdata_5
    DIRECTION OUTPUT ;
    USE SIGNAL ;
    ANTENNAGATEAREA 0.434700 ;
    ANTENNADIFFAREA 1.137600 ;
    PORT
      LAYER met3 ;
        RECT 231.320 119.720 231.920 120.320 ;
    END
  END mem_wdata_5
  PIN mem_wdata_6
    DIRECTION OUTPUT ;
    USE SIGNAL ;
    ANTENNAGATEAREA 0.434700 ;
    ANTENNADIFFAREA 1.137600 ;
    PORT
      LAYER met2 ;
        RECT 188.690 0.000 188.970 0.280 ;
    END
  END mem_wdata_6
  PIN mem_wdata_7
    DIRECTION OUTPUT ;
    USE SIGNAL ;
    ANTENNAGATEAREA 0.434700 ;
    ANTENNADIFFAREA 1.137600 ;
    PORT
      LAYER met3 ;
        RECT 231.320 110.200 231.920 110.800 ;
    END
  END mem_wdata_7
  PIN mem_wdata_8
    DIRECTION OUTPUT ;
    USE SIGNAL ;
    ANTENNAGATEAREA 0.434700 ;
    ANTENNADIFFAREA 1.137600 ;
    PORT
      LAYER met2 ;
        RECT 119.690 0.000 119.970 0.280 ;
    END
  END mem_wdata_8
  PIN mem_wdata_9
    DIRECTION OUTPUT ;
    USE SIGNAL ;
    ANTENNAGATEAREA 0.434700 ;
    ANTENNADIFFAREA 1.137600 ;
    PORT
      LAYER met3 ;
        RECT 231.320 95.240 231.920 95.840 ;
    END
  END mem_wdata_9
  PIN mem_wstrb_0
    DIRECTION OUTPUT ;
    USE SIGNAL ;
    ANTENNAGATEAREA 0.434700 ;
    ANTENNADIFFAREA 1.137600 ;
    PORT
      LAYER met3 ;
        RECT 231.320 175.480 231.920 176.080 ;
    END
  END mem_wstrb_0
  PIN mem_wstrb_1
    DIRECTION OUTPUT ;
    USE SIGNAL ;
    ANTENNAGATEAREA 0.434700 ;
    ANTENNADIFFAREA 1.137600 ;
    PORT
      LAYER met3 ;
        RECT 231.320 193.160 231.920 193.760 ;
    END
  END mem_wstrb_1
  PIN mem_wstrb_2
    DIRECTION OUTPUT ;
    USE SIGNAL ;
    ANTENNAGATEAREA 0.434700 ;
    ANTENNADIFFAREA 1.137600 ;
    PORT
      LAYER met3 ;
        RECT 231.320 186.360 231.920 186.960 ;
    END
  END mem_wstrb_2
  PIN mem_wstrb_3
    DIRECTION OUTPUT ;
    USE SIGNAL ;
    ANTENNAGATEAREA 0.434700 ;
    ANTENNADIFFAREA 1.137600 ;
    PORT
      LAYER met3 ;
        RECT 231.320 174.120 231.920 174.720 ;
    END
  END mem_wstrb_3
  PIN rst_n
    DIRECTION INPUT ;
    USE SIGNAL ;
    ANTENNAGATEAREA 0.647700 ;
    ANTENNADIFFAREA 0.434700 ;
    PORT
      LAYER met3 ;
        RECT 0.000 199.960 0.600 200.560 ;
    END
  END rst_n
  OBS
      LAYER nwell ;
        RECT 5.330 10.795 226.510 231.390 ;
      LAYER li1 ;
        RECT 5.520 10.795 226.320 231.285 ;
      LAYER met1 ;
        RECT 5.520 10.640 226.320 233.540 ;
      LAYER met2 ;
        RECT 6.070 242.080 19.130 242.360 ;
        RECT 19.970 242.080 23.730 242.360 ;
        RECT 24.570 242.080 24.650 242.360 ;
        RECT 25.490 242.080 30.170 242.360 ;
        RECT 31.010 242.080 32.010 242.360 ;
        RECT 32.850 242.080 40.290 242.360 ;
        RECT 41.130 242.080 41.210 242.360 ;
        RECT 42.050 242.080 42.130 242.360 ;
        RECT 42.970 242.080 43.050 242.360 ;
        RECT 43.890 242.080 43.970 242.360 ;
        RECT 44.810 242.080 44.890 242.360 ;
        RECT 45.730 242.080 83.530 242.360 ;
        RECT 84.370 242.080 84.450 242.360 ;
        RECT 85.290 242.080 90.890 242.360 ;
        RECT 91.730 242.080 92.730 242.360 ;
        RECT 93.570 242.080 100.090 242.360 ;
        RECT 100.930 242.080 103.770 242.360 ;
        RECT 104.610 242.080 109.290 242.360 ;
        RECT 110.130 242.080 110.210 242.360 ;
        RECT 111.050 242.080 114.810 242.360 ;
        RECT 115.650 242.080 117.570 242.360 ;
        RECT 118.410 242.080 126.770 242.360 ;
        RECT 127.610 242.080 129.530 242.360 ;
        RECT 130.370 242.080 130.450 242.360 ;
        RECT 131.290 242.080 131.370 242.360 ;
        RECT 132.210 242.080 135.050 242.360 ;
        RECT 135.890 242.080 135.970 242.360 ;
        RECT 136.810 242.080 136.890 242.360 ;
        RECT 137.730 242.080 148.850 242.360 ;
        RECT 149.690 242.080 151.610 242.360 ;
        RECT 152.450 242.080 153.450 242.360 ;
        RECT 154.290 242.080 157.130 242.360 ;
        RECT 157.970 242.080 158.050 242.360 ;
        RECT 158.890 242.080 172.770 242.360 ;
        RECT 173.610 242.080 175.530 242.360 ;
        RECT 176.370 242.080 176.450 242.360 ;
        RECT 177.290 242.080 178.290 242.360 ;
        RECT 179.130 242.080 181.970 242.360 ;
        RECT 182.810 242.080 182.890 242.360 ;
        RECT 183.730 242.080 225.310 242.360 ;
        RECT 6.070 0.560 225.310 242.080 ;
        RECT 6.170 0.070 6.250 0.560 ;
        RECT 7.090 0.070 7.170 0.560 ;
        RECT 8.010 0.070 8.090 0.560 ;
        RECT 8.930 0.070 9.010 0.560 ;
        RECT 9.850 0.070 9.930 0.560 ;
        RECT 10.770 0.070 10.850 0.560 ;
        RECT 11.690 0.070 11.770 0.560 ;
        RECT 12.610 0.070 12.690 0.560 ;
        RECT 13.530 0.070 13.610 0.560 ;
        RECT 14.450 0.070 14.530 0.560 ;
        RECT 15.370 0.070 15.450 0.560 ;
        RECT 16.290 0.070 16.370 0.560 ;
        RECT 17.210 0.070 17.290 0.560 ;
        RECT 18.130 0.070 18.210 0.560 ;
        RECT 19.050 0.070 19.130 0.560 ;
        RECT 19.970 0.070 20.050 0.560 ;
        RECT 20.890 0.070 20.970 0.560 ;
        RECT 21.810 0.070 21.890 0.560 ;
        RECT 22.730 0.070 22.810 0.560 ;
        RECT 23.650 0.070 23.730 0.560 ;
        RECT 24.570 0.070 24.650 0.560 ;
        RECT 25.490 0.070 25.570 0.560 ;
        RECT 26.410 0.070 26.490 0.560 ;
        RECT 27.330 0.070 27.410 0.560 ;
        RECT 28.250 0.070 28.330 0.560 ;
        RECT 29.170 0.070 29.250 0.560 ;
        RECT 30.090 0.070 30.170 0.560 ;
        RECT 31.010 0.070 31.090 0.560 ;
        RECT 31.930 0.070 32.010 0.560 ;
        RECT 32.850 0.070 32.930 0.560 ;
        RECT 33.770 0.070 33.850 0.560 ;
        RECT 34.690 0.070 34.770 0.560 ;
        RECT 35.610 0.070 35.690 0.560 ;
        RECT 36.530 0.070 36.610 0.560 ;
        RECT 37.450 0.070 37.530 0.560 ;
        RECT 38.370 0.070 38.450 0.560 ;
        RECT 39.290 0.070 39.370 0.560 ;
        RECT 40.210 0.070 40.290 0.560 ;
        RECT 41.130 0.070 41.210 0.560 ;
        RECT 42.050 0.070 42.130 0.560 ;
        RECT 42.970 0.070 43.050 0.560 ;
        RECT 43.890 0.070 43.970 0.560 ;
        RECT 44.810 0.070 44.890 0.560 ;
        RECT 45.730 0.070 45.810 0.560 ;
        RECT 46.650 0.070 46.730 0.560 ;
        RECT 47.570 0.070 47.650 0.560 ;
        RECT 48.490 0.070 48.570 0.560 ;
        RECT 49.410 0.070 49.490 0.560 ;
        RECT 50.330 0.070 50.410 0.560 ;
        RECT 51.250 0.070 51.330 0.560 ;
        RECT 52.170 0.070 52.250 0.560 ;
        RECT 53.090 0.070 53.170 0.560 ;
        RECT 54.010 0.070 54.090 0.560 ;
        RECT 54.930 0.070 55.010 0.560 ;
        RECT 55.850 0.070 55.930 0.560 ;
        RECT 56.770 0.070 56.850 0.560 ;
        RECT 57.690 0.070 57.770 0.560 ;
        RECT 58.610 0.070 58.690 0.560 ;
        RECT 59.530 0.070 59.610 0.560 ;
        RECT 60.450 0.070 78.930 0.560 ;
        RECT 79.770 0.070 87.210 0.560 ;
        RECT 88.050 0.070 92.730 0.560 ;
        RECT 93.570 0.070 98.250 0.560 ;
        RECT 99.090 0.070 99.170 0.560 ;
        RECT 100.010 0.070 106.530 0.560 ;
        RECT 107.370 0.070 111.130 0.560 ;
        RECT 111.970 0.070 118.490 0.560 ;
        RECT 119.330 0.070 119.410 0.560 ;
        RECT 120.250 0.070 120.330 0.560 ;
        RECT 121.170 0.070 121.250 0.560 ;
        RECT 122.090 0.070 123.090 0.560 ;
        RECT 123.930 0.070 127.690 0.560 ;
        RECT 128.530 0.070 128.610 0.560 ;
        RECT 129.450 0.070 130.450 0.560 ;
        RECT 131.290 0.070 135.050 0.560 ;
        RECT 135.890 0.070 140.570 0.560 ;
        RECT 141.410 0.070 143.330 0.560 ;
        RECT 144.170 0.070 147.010 0.560 ;
        RECT 147.850 0.070 185.650 0.560 ;
        RECT 186.490 0.070 186.570 0.560 ;
        RECT 187.410 0.070 187.490 0.560 ;
        RECT 188.330 0.070 188.410 0.560 ;
        RECT 189.250 0.070 189.330 0.560 ;
        RECT 190.170 0.070 190.250 0.560 ;
        RECT 191.090 0.070 191.170 0.560 ;
        RECT 192.010 0.070 192.090 0.560 ;
        RECT 192.930 0.070 193.010 0.560 ;
        RECT 193.850 0.070 195.770 0.560 ;
        RECT 196.610 0.070 196.690 0.560 ;
        RECT 197.530 0.070 197.610 0.560 ;
        RECT 198.450 0.070 198.530 0.560 ;
        RECT 199.370 0.070 199.450 0.560 ;
        RECT 200.290 0.070 225.310 0.560 ;
      LAYER met3 ;
        RECT 0.600 202.320 231.320 231.365 ;
        RECT 1.000 199.560 231.320 202.320 ;
        RECT 0.600 194.160 231.320 199.560 ;
        RECT 0.600 192.760 230.920 194.160 ;
        RECT 0.600 187.360 231.320 192.760 ;
        RECT 0.600 185.960 230.920 187.360 ;
        RECT 0.600 180.560 231.320 185.960 ;
        RECT 0.600 177.800 230.920 180.560 ;
        RECT 0.600 176.480 231.320 177.800 ;
        RECT 0.600 173.720 230.920 176.480 ;
        RECT 0.600 172.400 231.320 173.720 ;
        RECT 1.000 171.000 231.320 172.400 ;
        RECT 0.600 169.680 231.320 171.000 ;
        RECT 1.000 168.280 230.920 169.680 ;
        RECT 1.000 166.920 231.320 168.280 ;
        RECT 0.600 165.600 231.320 166.920 ;
        RECT 1.000 162.880 231.320 165.600 ;
        RECT 1.000 162.840 230.920 162.880 ;
        RECT 0.600 161.480 230.920 162.840 ;
        RECT 0.600 160.160 231.320 161.480 ;
        RECT 1.000 158.760 231.320 160.160 ;
        RECT 0.600 157.440 231.320 158.760 ;
        RECT 0.600 156.040 230.920 157.440 ;
        RECT 0.600 154.720 231.320 156.040 ;
        RECT 1.000 153.320 231.320 154.720 ;
        RECT 0.600 152.000 231.320 153.320 ;
        RECT 1.000 150.600 231.320 152.000 ;
        RECT 0.600 149.280 231.320 150.600 ;
        RECT 1.000 147.880 231.320 149.280 ;
        RECT 0.600 145.200 231.320 147.880 ;
        RECT 1.000 141.120 231.320 145.200 ;
        RECT 1.000 139.720 230.920 141.120 ;
        RECT 1.000 138.400 231.320 139.720 ;
        RECT 1.000 137.000 230.920 138.400 ;
        RECT 1.000 135.640 231.320 137.000 ;
        RECT 0.600 134.320 231.320 135.640 ;
        RECT 1.000 132.920 230.920 134.320 ;
        RECT 1.000 131.560 231.320 132.920 ;
        RECT 0.600 127.520 231.320 131.560 ;
        RECT 0.600 124.800 230.920 127.520 ;
        RECT 1.000 124.760 230.920 124.800 ;
        RECT 1.000 123.440 231.320 124.760 ;
        RECT 1.000 122.040 230.920 123.440 ;
        RECT 0.600 120.720 231.320 122.040 ;
        RECT 1.000 119.320 230.920 120.720 ;
        RECT 0.600 118.000 231.320 119.320 ;
        RECT 1.000 111.160 230.920 118.000 ;
        RECT 0.600 108.480 230.920 111.160 ;
        RECT 1.000 107.080 230.920 108.480 ;
        RECT 0.600 103.000 230.920 107.080 ;
        RECT 0.600 101.680 231.320 103.000 ;
        RECT 1.000 100.280 231.320 101.680 ;
        RECT 0.600 96.240 231.320 100.280 ;
        RECT 0.600 94.840 230.920 96.240 ;
        RECT 0.600 93.520 231.320 94.840 ;
        RECT 1.000 92.120 231.320 93.520 ;
        RECT 0.600 90.800 231.320 92.120 ;
        RECT 1.000 83.960 230.920 90.800 ;
        RECT 0.600 82.640 230.920 83.960 ;
        RECT 1.000 81.240 230.920 82.640 ;
        RECT 0.600 79.880 230.920 81.240 ;
        RECT 0.600 75.840 231.320 79.880 ;
        RECT 0.600 74.440 230.920 75.840 ;
        RECT 0.600 10.715 231.320 74.440 ;
      LAYER met4 ;
        RECT 26.975 66.135 27.305 106.585 ;
  END
END dcache
END LIBRARY

